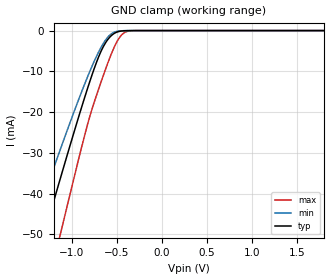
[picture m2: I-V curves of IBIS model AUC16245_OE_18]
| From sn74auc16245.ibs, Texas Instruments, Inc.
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[Model]   AUC16245_OE_18
Model_type  Input
Vinl=0.5775
Vinh=1.2675
| variable   typ   min   max
C_comp   2.32pF   1.95pF   2.89pF
[Temperature Range]   40   100   -40
| Ambient temperature   25   85   -40
[Voltage range]   1.8   1.65   1.95
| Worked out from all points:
|   GND clamp passes 1 mA (typ) near -0.55 V on its own axis
[GND Clamp]
| AUC16245_OE_18
|   Voltage   I(typ)   I(min)   I(max)
-3.6V     -230.2mA   -193.8mA   -275.4mA
-1.445V   -60.91mA   -49.39mA   -79.48mA
-1.29V    -48.93mA   -39.5mA    -65.22mA
-1.145V   -37.84mA   -30.41mA   -51.89mA
-1.1V     -34.44mA   -27.64mA   -47.76mA
-830mV    -14.72mA   -11.79mA   -23.67mA
-690mV    -5.96mA    -4.844mA   -13.74mA
-565mV    -1.381mA   -914.2uA   -6.102mA
-490mV    -326uA     -167.9uA   -2.495mA
-425mV    -63.97uA   -31.34uA   -688.8uA
-275mV    -662.6nA   -487.6nA   -4.372uA
1.8V      203.2pA    298.4pA    235.5pA
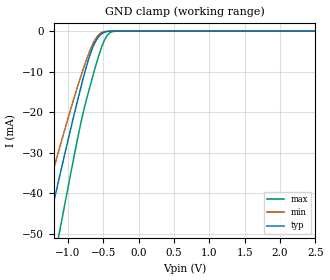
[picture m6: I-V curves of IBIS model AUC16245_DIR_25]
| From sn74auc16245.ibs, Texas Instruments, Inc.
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[Model]   AUC16245_DIR_25
Model_type  Input
Vinl=0.7
Vinh=1.7
| variable   typ   min   max
C_comp   2.33pF   1.93pF   2.84pF
[Temperature Range]   40   100   -40
| Ambient temperature   25   85   -40
[Voltage range]   2.5   2.3   2.7
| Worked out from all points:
|   GND clamp passes 1 mA (typ) near -0.55 V on its own axis
[GND Clamp]
| AUC16245_DIR_25
|   Voltage   I(typ)   I(min)   I(max)
-3.6V     -230.2mA   -193.8mA   -275.4mA
-1.465V   -62.46mA   -50.68mA   -81.32mA
-1.41V    -58.19mA   -47.14mA   -76.26mA
-1.3V     -49.69mA   -40.13mA   -66.14mA
-1.11V    -35.19mA   -28.25mA   -48.67mA
-845mV    -15.76mA   -12.61mA   -24.92mA
-720mV    -7.623mA   -6.181mA   -15.69mA
-625mV    -3.09mA    -2.403mA   -9.633mA
-515mV    -559.5uA   -308.9uA   -3.552mA
-430mV    -73.2uA    -35.77uA   -776.9uA
-325mV    -3.339uA   -2.035uA   -30.74uA
2.5V      313.9pA    402pA      470.4pA
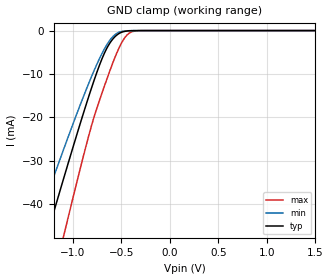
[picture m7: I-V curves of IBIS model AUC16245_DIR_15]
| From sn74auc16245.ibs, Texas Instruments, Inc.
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[Model]   AUC16245_DIR_15
Model_type  Input
Vinl=0.49
Vinh=1.04
| variable   typ   min   max
C_comp   2.33pF   1.94pF   2.89pF
[Temperature Range]   40   100   -40
| Ambient temperature   25   85   -40
[Voltage range]   1.5   1.4   1.6
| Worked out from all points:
|   GND clamp passes 1 mA (typ) near -0.55 V on its own axis
[GND Clamp]
| AUC16245_DIR_15
|   Voltage   I(typ)   I(min)   I(max)
-3.6V     -230.2mA   -193.8mA   -275.4mA
-1.39V    -56.64mA   -45.86mA   -74.42mA
-1.25V    -45.85mA   -36.97mA   -61.54mA
-1.095V   -34.06mA   -27.33mA   -47.3mA
-1.05V    -30.68mA   -24.59mA   -43.18mA
-810mV    -13.36mA   -10.7mA    -22.06mA
-685mV    -5.701mA   -4.633mA   -13.41mA
-565mV    -1.381mA   -914.2uA   -6.102mA
-490mV    -326uA     -167.9uA   -2.495mA
-425mV    -63.97uA   -31.34uA   -688.8uA
-280mV    -781.4nA   -563.5nA   -5.358uA
1.5V      165.9pA    259.7pA    172.1pA
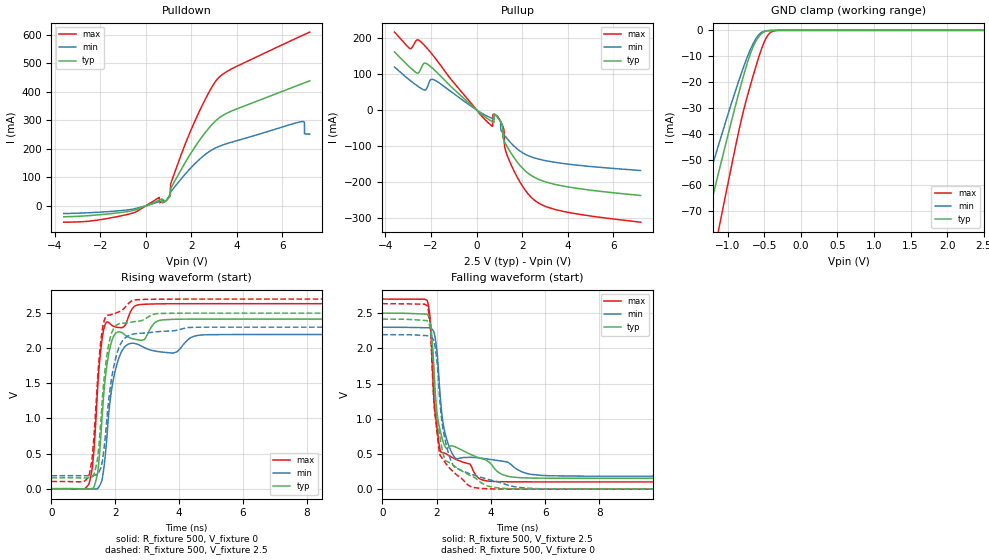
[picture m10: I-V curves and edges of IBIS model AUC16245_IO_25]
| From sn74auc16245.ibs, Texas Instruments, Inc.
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[Model]   AUC16245_IO_25
Model_type  3-state
Enable   Active-Low
Vref =   0
Rref =   500
Cref =   30p
Vmeas =   1.25
| variable   typ   min   max
C_comp   6.76pF   6.14pF   9.40pF
| C_pullup   6.70pF   2.16pF   10.57pF
| C_pulldown   7.47pF   4.10pF   11.73pF
| C_tri-state   6.76pF   6.14pF   9.40pF
[Temperature Range]   40   100   -40
| Ambient temperature   25   85   -40
[Voltage range]   2.5   2.3   2.7
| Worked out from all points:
|   slope of the pulldown table from 0 to 0.375 V, typ, clamps not added: 30.7 ohm
|   slope of the pullup table from 0 to 0.375 V, typ, clamps not added: 19 ohm
|   GND clamp passes 1 mA (typ) near -0.52 V on its own axis
|   rising waveform, R_fixture 500, V_fixture 0: 20-80 % time 296ps typ, 363ps min, 254ps max; typ from 0 V to 2.42 V
|   falling waveform, R_fixture 500, V_fixture 2.5: 20-80 % time 438ps typ, 426ps min, 301ps max; typ from 2.5 V to 0.155 V
|   rising waveform, R_fixture 500, V_fixture 2.5: 20-80 % time 296ps typ, 366ps min, 256ps max; typ from 0.154 V to 2.5 V
|   falling waveform, R_fixture 500, V_fixture 0: 20-80 % time 400ps typ, 469ps min, 308ps max; typ from 2.42 V to 0 V
[GND Clamp]
| AUC16245_IO_25
|   Voltage   I(typ)   I(min)   I(max)
-3.6V     -349.5mA   -293.4mA   -425.3mA
-1.46V    -94.2mA    -76.43mA   -124.8mA
-1.405V   -87.72mA   -71.07mA   -117mA
-1.295V   -74.83mA   -60.46mA   -101.4mA
-1.105V   -52.83mA   -42.49mA   -74.46mA
-850mV    -24.45mA   -19.66mA   -39.23mA
-725mV    -12.02mA   -9.83mA    -24.81mA
-625mV    -4.709mA   -3.708mA   -14.93mA
-520mV    -952.5uA   -548.5uA   -5.863mA
-430mV    -113.4uA   -65.08uA   -1.204mA
-325mV    -5.32uA    -5.774uA   -47.72uA
2.5V      1.104nA    211.9nA    1.576nA
[Pulldown]
| AUC16245_IO_25
|   Voltage   I(typ)   I(min)   I(max)
-3.6V     -38.1mA    -26.84mA   -57.15mA
-1.09V    -23.1mA    -16.55mA   -35.1mA
590mV     19.92mA    14.98mA    30.03mA
600mV     20.28mA    15.25mA    11.17mA
910mV     20.16mA    20.33mA    19.24mA
1.07V     37.88mA    45.66mA    41.07mA
1.915V    176.4mA    127.8mA    252.5mA
3.135V    303.2mA    205.9mA    444mA
6.825V    427.4mA    295.5mA    596mA
6.965V    431.7mA    292.5mA    601.1mA
6.97V     431.8mA    252.7mA    601.3mA
7.2V      438.7mA    251.9mA    609.7mA
[Pullup]
| AUC16245_IO_25
|   Voltage   I(typ)   I(min)   I(max)
-3.6V     161.4mA    119.4mA    216.5mA
-2.915V   117.9mA    81.99mA    170.3mA
-2.395V   121.2mA    58.44mA    186.4mA
-1.87V    112.4mA    83.85mA    148.4mA
655mV     -31.14mA   -22.54mA   -43.43mA
935mV     -20.74mA   -21.43mA   -18.64mA
1.135V    -41.07mA   -62.77mA   -43.34mA
1.19V     -83.17mA   -67.47mA   -51.41mA
1.235V    -89.46mA   -71.21mA   -103.5mA
1.485V    -117.1mA   -90.17mA   -147.8mA
2.56V     -187.9mA   -133.6mA   -251.8mA
7.2V      -237.7mA   -168.2mA   -311.9mA
[Ramp]
| AUC16245_IO_25
| variable   typ   min   max
dV/dt_r   1.45/3.09E-10   1.32/3.65E-10   1.58/2.62E-10
dV/dt_f   1.41/4.44E-10   1.27/4.28E-10   1.56/3.06E-10
R_load = 500
[Rising Waveform]
| AUC16245_IO_25
R_fixture =   500
C_fixture =   0
L_fixture =   0
V_fixture =   0
V_fixture_min = 0
V_fixture_max = 0
|   Time   V(typ)   V(min)   V(max)
0s        13.18nV    38.22nV    2.947nV
1.175ns   -4.672mV   -3.905mV   66.19mV
1.315ns   7.873mV    -4.517mV   459.2mV
1.495ns   429.4mV    30.29mV    1.734V
1.68ns    1.547V     438.9mV    2.334V
1.895ns   2.11V      1.437V     2.326V
2.23ns    2.216V     1.978V     2.295V
2.72ns    2.12V      2.053V     2.618V
3.85ns    2.412V     1.935V     2.634V
34.99ns   2.416V     2.195V     2.634V
[Falling Waveform]
| AUC16245_IO_25
R_fixture =   500
C_fixture =   0
L_fixture =   0
V_fixture =   2.5
V_fixture_min = 2.3
V_fixture_max = 2.7
|   Time   V(typ)   V(min)   V(max)
0s        2.5V       2.3V       2.7V
1.655ns   2.486V     2.293V     2.68V
1.765ns   2.395V     2.293V     2.427V
1.93ns    1.514V     2.192V     1.151V
2.14ns    822.6mV    1.305V     543.1mV
2.31ns    609.1mV    799.2mV    509.7mV
2.655ns   605.9mV    457.4mV    433.9mV
3.795ns   418.5mV    432.1mV    121.6mV
5.49ns    158.1mV    210mV      103mV
34.99ns   154.5mV    184.4mV    102.7mV
[Rising Waveform]
| AUC16245_IO_25
R_fixture =   500
C_fixture =   0
L_fixture =   0
V_fixture =   2.5
V_fixture_min = 2.3
V_fixture_max = 2.7
|   Time   V(typ)   V(min)   V(max)
0s        154.5mV    184.4mV    102.6mV
1.17ns    156.7mV    184.8mV    177.1mV
1.3ns     174.9mV    188.9mV    554.6mV
1.475ns   550.7mV    224.7mV    1.745V
1.635ns   1.494V     520.8mV    2.36V
1.85ns    2.164V     1.464V     2.476V
2.14ns    2.351V     2.035V     2.522V
2.58ns    2.377V     2.203V     2.686V
3.84ns    2.498V     2.249V     2.7V
34.99ns   2.5V       2.3V       2.7V
[Falling Waveform]
| AUC16245_IO_25
R_fixture =   500
C_fixture =   0
L_fixture =   0
V_fixture =   0
V_fixture_min = 0
V_fixture_max = 0
|   Time   V(typ)   V(min)   V(max)
0s        2.416V     2.195V     2.634V
1.655ns   2.393V     2.179V     2.605V
1.765ns   2.301V     2.175V     2.345V
1.92ns    1.52V      2.082V     1.147V
2.12ns    756.6mV    1.269V     496.9mV
2.29ns    441.3mV    745.5mV    393.1mV
2.57ns    351.2mV    371.5mV    263.3mV
3.4ns     164.7mV    196.6mV    22.12mV
6.15ns    426.2uV    3.571mV    75.73uV
34.99ns   54.94uV    69.81uV    13.22uV
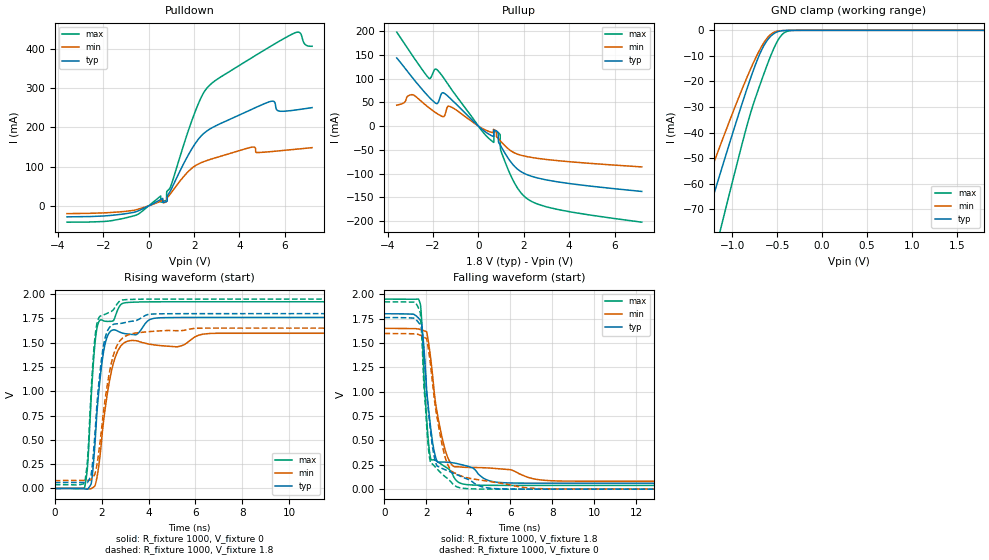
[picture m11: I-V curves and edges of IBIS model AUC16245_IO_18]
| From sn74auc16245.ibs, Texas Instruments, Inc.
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[Model]   AUC16245_IO_18
Model_type  3-state
Enable   Active-Low
Vref =   0
Rref =   1000
Cref =   30p
Vmeas =   0.9
| variable   typ   min   max
C_comp   8.31pF   6.42pF   13.81pF
| C_pullup   7.29pF   1.43pF   13.89pF
| C_pulldown   10.32pF   6.63pF   16.50pF
| C_tri-state   8.31pF   6.42pF   13.81pF
[Temperature Range]   40   100   -40
| Ambient temperature   25   85   -40
[Voltage range]   1.8   1.65   1.95
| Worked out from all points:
|   slope of the pulldown table from 0 to 0.27 V, typ, clamps not added: 34.2 ohm
|   slope of the pullup table from 0 to 0.27 V, typ, clamps not added: 24.6 ohm
|   GND clamp passes 1 mA (typ) near -0.52 V on its own axis
|   rising waveform, R_fixture 1000, V_fixture 0: 20-80 % time 401ps typ, 568ps min, 296ps max; typ from 0 V to 1.76 V
|   falling waveform, R_fixture 1000, V_fixture 1.8: 20-80 % time 473ps typ, 700ps min, 318ps max; typ from 1.8 V to 0.061 V
|   rising waveform, R_fixture 1000, V_fixture 1.8: 20-80 % time 401ps typ, 571ps min, 291ps max; typ from 0.061 V to 1.8 V
|   falling waveform, R_fixture 1000, V_fixture 0: 20-80 % time 476ps typ, 713ps min, 328ps max; typ from 1.76 V to 0 V
[GND Clamp]
| AUC16245_IO_18
|   Voltage   I(typ)   I(min)   I(max)
-3.6V     -349.5mA   -293.4mA   -425.3mA
-1.5V     -98.92mA   -80.33mA   -130.5mA
-1.445V   -92.43mA   -74.96mA   -122.7mA
-1.29V    -74.25mA   -59.98mA   -100.7mA
-1.145V   -57.42mA   -46.23mA   -80.12mA
-1.1V     -52.26mA   -42.02mA   -73.75mA
-840mV    -23.39mA   -18.82mA   -37.93mA
-690mV    -9.056mA   -7.439mA   -21.28mA
-565mV    -2.115mA   -1.422mA   -9.456mA
-490mV    -502.9uA   -270.8uA   -3.866mA
-425mV    -99.1uA    -58.01uA   -1.068mA
1.8V      714.1pA    45.22nA    788.6pA
[Pulldown]
| AUC16245_IO_18
|   Voltage   I(typ)   I(min)   I(max)
-3.6V     -28.02mA   -19.77mA   -41.62mA
-1.105V   -20.75mA   -14.51mA   -31.96mA
530mV     16.28mA    11.83mA    25.26mA
780mV     11.06mA    10.81mA    14.1mA
800mV     11.7mA     11.72mA    36.72mA
1.955V    150.3mA    98.42mA    225.9mA
2.625V    193.2mA    116.8mA    304mA
4.56V     246.5mA    149.8mA    378.1mA
5.38V     266.3mA    138.3mA    406.9mA
5.71V     242.1mA    140mA      418.1mA
6.445V    244.1mA    144.1mA    441mA
7.2V      250.4mA    148.3mA    406.7mA
[Pullup]
| AUC16245_IO_18
|   Voltage   I(typ)   I(min)   I(max)
-3.6V     143.4mA    44.01mA    197.6mA
-2.93V    103.2mA    66.14mA    150mA
-2.195V   61.97mA    39.18mA    101.3mA
-1.91V    49.09mA    29.08mA    119.7mA
-1.255V   58.85mA    41.38mA    81.92mA
440mV     -16.41mA   -10.86mA   -25.07mA
840mV     -11.85mA   -24.43mA   -13.19mA
930mV     -37.45mA   -29.05mA   -16.21mA
980mV     -41.44mA   -31.73mA   -49.64mA
1.305V    -67.24mA   -47.38mA   -90.82mA
2.11V     -101.4mA   -63.86mA   -151.3mA
7.2V      -137.4mA   -85.82mA   -202mA
[Ramp]
| AUC16245_IO_18
| variable   typ   min   max
dV/dt_r   1.06/4.06E-10   0.96/5.72E-10   1.16/3.06E-10
dV/dt_f   1.04/4.95E-10   0.94/7.15E-10   1.15/3.22E-10
R_load = 1000
[Rising Waveform]
| AUC16245_IO_18
R_fixture =   1000
C_fixture =   0
L_fixture =   0
V_fixture =   0
V_fixture_min = 0
V_fixture_max = 0
|   Time   V(typ)   V(min)   V(max)
0s        10.28nV    34.85nV    1.692nV
1.27ns    -4.208mV   -985.1uV   6.222mV
1.395ns   -6.957mV   -2.921mV   220.7mV
1.55ns    44.96mV    -1.425mV   916mV
1.715ns   462mV      26.46mV    1.493V
1.93ns    1.123V     336.8mV    1.733V
2.175ns   1.516V     866.7mV    1.721V
2.54ns    1.633V     1.321V     1.745V
2.975ns   1.595V     1.502V     1.911V
34.99ns   1.761V     1.597V     1.922V
[Falling Waveform]
| AUC16245_IO_18
R_fixture =   1000
C_fixture =   0
L_fixture =   0
V_fixture =   1.8
V_fixture_min = 1.65
V_fixture_max = 1.95
|   Time   V(typ)   V(min)   V(max)
0s        1.8V       1.65V      1.95V
1.65ns    1.749V     1.641V     1.938V
1.79ns    1.664V     1.633V     1.654V
1.915ns   1.345V     1.623V     1.019V
2.205ns   624.4mV    1.337V     310.5mV
2.495ns   292.2mV    804.6mV    286.6mV
2.9ns     277.6mV    398.5mV    229.1mV
3.71ns    249.5mV    226mV      54.39mV
5.84ns    64.39mV    202.6mV    38.82mV
34.99ns   61.1mV     81.06mV    38.7mV
[Rising Waveform]
| AUC16245_IO_18
R_fixture =   1000
C_fixture =   0
L_fixture =   0
V_fixture =   1.8
V_fixture_min = 1.65
V_fixture_max = 1.95
|   Time   V(typ)   V(min)   V(max)
0s        61.05mV    81.01mV    38.68mV
1.27ns    60.95mV    83.35mV    50.9mV
1.395ns   61.26mV    84.19mV    292.6mV
1.555ns   145.2mV    94.77mV    1.019V
1.79ns    839.7mV    234.2mV    1.686V
1.99ns    1.326V     596.8mV    1.78V
2.18ns    1.578V     970.6mV    1.797V
2.5ns     1.689V     1.372V     1.841V
2.88ns    1.702V     1.545V     1.94V
34.99ns   1.8V       1.65V      1.95V
[Falling Waveform]
| AUC16245_IO_18
R_fixture =   1000
C_fixture =   0
L_fixture =   0
V_fixture =   0
V_fixture_min = 0
V_fixture_max = 0
|   Time   V(typ)   V(min)   V(max)
0s        1.761V     1.597V     1.922V
1.655ns   1.702V     1.584V     1.842V
1.8ns     1.595V     1.57V      1.466V
2.04ns    915.7mV    1.507V     560.1mV
2.185ns   615.6mV    1.291V     279.9mV
2.46ns    260.7mV    795mV      218.4mV
2.845ns   203.5mV    365.5mV    136.4mV
3.575ns   137.3mV    142.6mV    15.17mV
5.66ns    2.6mV      57.6mV     229.1uV
34.99ns   49.39uV    55.17uV    15.06uV
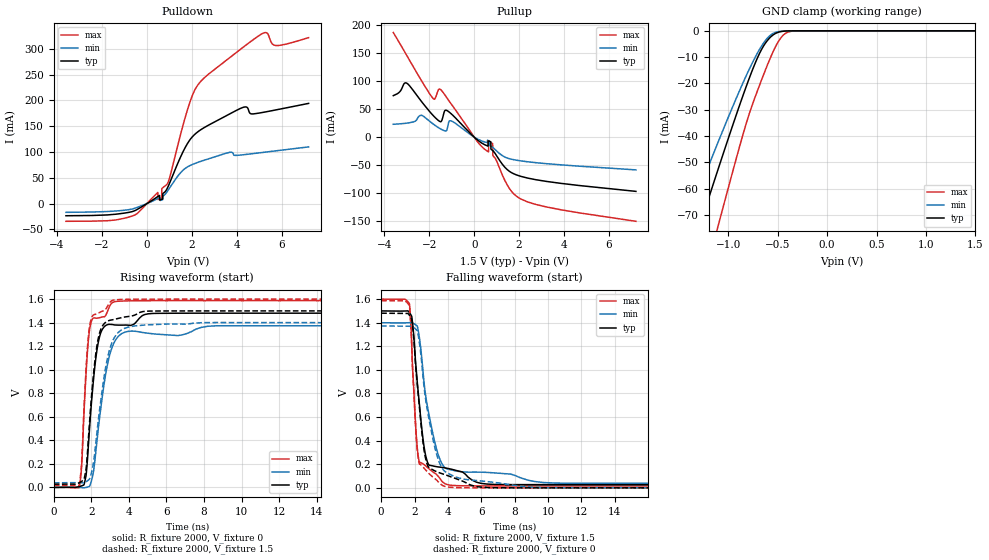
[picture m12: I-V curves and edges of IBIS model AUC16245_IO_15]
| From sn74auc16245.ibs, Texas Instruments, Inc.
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[Model]   AUC16245_IO_15
Model_type  3-state
Enable   Active-Low
Vref =   0
Rref =   2000
Cref =   15p
Vmeas =   0.75
| variable   typ   min   max
C_comp   9.39pF   6.58pF   15.81pF
| C_pullup   8.72pF   0.18pF   19.61pF
| C_pulldown   12.05pF   6.85pF   19.33pF
| C_tri-state   9.39pF   6.58pF   15.81pF
[Temperature Range]   40   100   -40
| Ambient temperature   25   85   -40
[Voltage range]   1.5   1.4   1.6
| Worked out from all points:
|   slope of the pulldown table from 0 to 0.225 V, typ, clamps not added: 37.2 ohm
|   slope of the pullup table from 0 to 0.225 V, typ, clamps not added: 30 ohm
|   GND clamp passes 1 mA (typ) near -0.52 V on its own axis
|   rising waveform, R_fixture 2000, V_fixture 0: 20-80 % time 500ps typ, 714ps min, 328ps max; typ from 0 V to 1.48 V
|   falling waveform, R_fixture 2000, V_fixture 1.5: 20-80 % time 603ps typ, 941ps min, 354ps max; typ from 1.5 V to 0.027 V
|   rising waveform, R_fixture 2000, V_fixture 1.5: 20-80 % time 495ps typ, 709ps min, 322ps max; typ from 0.027 V to 1.5 V
|   falling waveform, R_fixture 2000, V_fixture 0: 20-80 % time 603ps typ, 942ps min, 353ps max; typ from 1.48 V to 0 V
[GND Clamp]
| AUC16245_IO_15
|   Voltage   I(typ)   I(min)   I(max)
-3.6V     -349.5mA   -293.4mA   -425.3mA
-1.42V    -89.49mA   -72.53mA   -119.2mA
-1.315V   -77.17mA   -62.38mA   -104.2mA
-1.265V   -71.33mA   -57.59mA   -97.15mA
-1.125V   -55.12mA   -44.35mA   -77.29mA
-1.085V   -50.54mA   -40.63mA   -71.64mA
-835mV    -22.86mA   -18.41mA   -37.29mA
-685mV    -8.663mA   -7.116mA   -20.79mA
-565mV    -2.115mA   -1.422mA   -9.456mA
-490mV    -502.9uA   -270.8uA   -3.866mA
-425mV    -99.1uA    -58.01uA   -1.068mA
1.5V      582.6pA    9.424nA    576.2pA
[Pulldown]
| AUC16245_IO_15
|   Voltage   I(typ)   I(min)   I(max)
-3.6V     -23.47mA   -16.88mA   -34.23mA
-1.005V   -18.41mA   -12.79mA   -28.34mA
485mV     13.68mA    9.737mA    21.72mA
660mV     8.179mA    6.953mA    10.96mA
670mV     8.319mA    7.1mA      28.79mA
985mV     36.88mA    28.41mA    46.12mA
1.91V     123.2mA    73.57mA    195.6mA
2.415V    143.6mA    82.17mA    237.7mA
4.315V    187mA      94.84mA    304mA
5.195V    177.1mA    99.4mA     330.7mA
5.745V    181.6mA    102.3mA    306.4mA
7.2V      194.3mA    110mA      321.7mA
[Pullup]
| AUC16245_IO_15
|   Voltage   I(typ)   I(min)   I(max)
-3.6V     74mA       22.96mA    186.5mA
-2.995V   96.17mA    25mA       145.2mA
-2.36V    64.35mA    38.95mA    101.6mA
-1.825V   38.55mA    23.39mA    68.78mA
-1.505V   27.52mA    14.87mA    85.23mA
-1.21V    47.39mA    13.41mA    69.72mA
-1.025V   41.71mA    29.01mA    59.25mA
330mV     -10.46mA   -6.758mA   -16.68mA
820mV     -23.65mA   -18mA      -11.49mA
845mV     -24.61mA   -18.86mA   -33.67mA
1.87V     -67.21mA   -41.05mA   -105mA
7.2V      -96.75mA   -58.41mA   -150.1mA
[Ramp]
| AUC16245_IO_15
| variable   typ   min   max
dV/dt_r   0.89/5.08E-10   0.83/7.30E-10   0.95/3.40E-10
dV/dt_f   0.88/6.23E-10   0.82/9.74E-10   0.95/3.57E-10
R_load = 2000
[Rising Waveform]
| AUC16245_IO_15
R_fixture =   2000
C_fixture =   0
L_fixture =   0
V_fixture =   0
V_fixture_min = 0
V_fixture_max = 0
|   Time   V(typ)   V(min)   V(max)
0s        9.43nV     35.08nV    1.304nV
1.355ns   6.665mV    -48.16uV   908.3uV
1.48ns    13.06mV    -1.487mV   178.4mV
1.715ns   99.56mV    -281.2uV   961.8mV
1.915ns   526.1mV    13mV       1.349V
2.425ns   1.273V     575.3mV    1.442V
2.83ns    1.382V     1.022V     1.484V
3.23ns    1.381V     1.236V     1.578V
8.67ns    1.48V      1.373V     1.587V
34.99ns   1.481V     1.373V     1.587V
[Falling Waveform]
| AUC16245_IO_15
R_fixture =   2000
C_fixture =   0
L_fixture =   0
V_fixture =   1.5
V_fixture_min = 1.4
V_fixture_max = 1.6
|   Time   V(typ)   V(min)   V(max)
0s        1.5V       1.4V       1.6V
1.695ns   1.486V     1.4V       1.56V
1.88ns    1.398V     1.398V     1.025V
2.165ns   892.8mV    1.372V     335mV
2.51ns    410mV      980.5mV    203.5mV
2.765ns   222mV      695.2mV    173.9mV
3.385ns   178.2mV    295.3mV    103mV
3.925ns   166.8mV    161.1mV    29.29mV
6.81ns    29.06mV    126.6mV    16.53mV
34.99ns   27.22mV    38.8mV     16.42mV
[Rising Waveform]
| AUC16245_IO_15
R_fixture =   2000
C_fixture =   0
L_fixture =   0
V_fixture =   1.5
V_fixture_min = 1.4
V_fixture_max = 1.6
|   Time   V(typ)   V(min)   V(max)
0s        27.17mV    38.75mV    16.4mV
1.35ns    39.13mV    39.7mV     17.64mV
1.48ns    51.09mV    39.27mV    210.1mV
1.71ns    149.2mV    47.26mV    984.3mV
1.905ns   556.6mV    72.5mV     1.367V
2.395ns   1.285V     603.3mV    1.483V
2.785ns   1.406V     1.04V      1.519V
3.155ns   1.425V     1.251V     1.591V
7.925ns   1.5V       1.4V       1.6V
34.99ns   1.5V       1.4V       1.6V
[Falling Waveform]
| AUC16245_IO_15
R_fixture =   2000
C_fixture =   0
L_fixture =   0
V_fixture =   0
V_fixture_min = 0
V_fixture_max = 0
|   Time   V(typ)   V(min)   V(max)
0s        1.481V     1.373V     1.587V
1.695ns   1.462V     1.37V      1.544V
1.875ns   1.378V     1.366V     1.029V
2.165ns   873.9mV    1.332V     315.8mV
2.5ns     392mV      951.3mV    177.7mV
2.735ns   209.1mV    685.3mV    140.9mV
3.32ns    137.2mV    285.9mV    66.14mV
3.815ns   112.1mV    139.3mV    12.37mV
9.56ns    274.9uV    2.736mV    91.7uV
34.99ns   49.37uV    49.17uV    16.8uV
